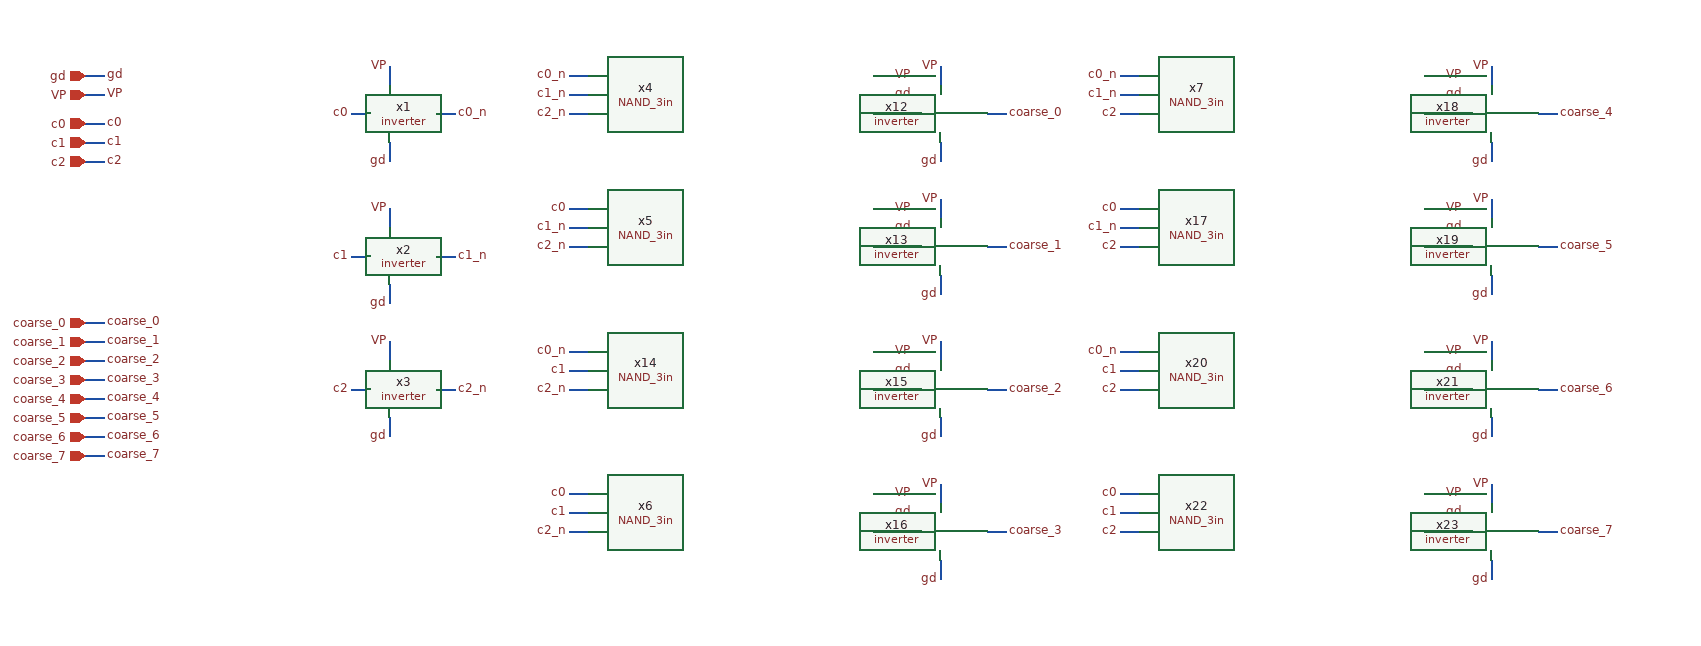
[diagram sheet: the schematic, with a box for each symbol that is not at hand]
v {xschem version=3.4.8RC file_version=1.3}
G {}
K {}
V {}
S {}
F {}
E {}
N 70 -40 90 -40 {lab=gd}
N 70 -20 90 -20 {lab=VP}
N 70 30 90 30 {lab=c1}
N 70 50 90 50 {lab=c2}
N 70 10 90 10 {lab=c0}
N 70 240 90 240 {lab=coarse_1}
N 70 260 90 260 {lab=coarse_2}
N 70 220 90 220 {lab=coarse_0}
N 70 280 90 280 {lab=coarse_3}
N 70 300 90 300 {lab=coarse_4}
N 70 340 90 340 {lab=coarse_6}
N 70 360 90 360 {lab=coarse_7}
N 70 320 90 320 {lab=coarse_5}
N 390 30 390 50 {lab=gd}
N 390 -50 390 -30 {lab=VP}
N 390 180 390 200 {lab=gd}
N 390 100 390 120 {lab=VP}
N 390 320 390 340 {lab=gd}
N 390 240 390 260 {lab=VP}
N 350 150 370 150 {lab=c1}
N 350 290 370 290 {lab=c2}
N 350 0 370 0 {lab=c0}
N 440 150 460 150 {lab=c1_n}
N 440 290 460 290 {lab=c2_n}
N 440 0 460 0 {lab=c0_n}
N 900 -40 920 -40 {lab=VP}
N 900 -20 920 -20 {lab=gd}
N 900 0 950 0 {lab=#net1}
N 580 -40 600 -40 {lab=c0_n}
N 580 -20 600 -20 {lab=c1_n}
N 580 0 600 0 {lab=c2_n}
N 900 100 920 100 {lab=VP}
N 900 120 920 120 {lab=gd}
N 900 140 950 140 {lab=#net2}
N 580 100 600 100 {lab=c0}
N 580 120 600 120 {lab=c1_n}
N 580 140 600 140 {lab=c2_n}
N 580 250 600 250 {lab=c0_n}
N 580 270 600 270 {lab=c1}
N 580 290 600 290 {lab=c2_n}
N 580 400 600 400 {lab=c0}
N 580 420 600 420 {lab=c1}
N 580 440 600 440 {lab=c2_n}
N 1160 100 1180 100 {lab=c0}
N 1160 120 1180 120 {lab=c1_n}
N 1160 140 1180 140 {lab=c2}
N 1160 250 1180 250 {lab=c0_n}
N 1160 270 1180 270 {lab=c1}
N 1160 290 1180 290 {lab=c2}
N 1160 400 1180 400 {lab=c0}
N 1160 420 1180 420 {lab=c1}
N 1160 440 1180 440 {lab=c2}
N 970 30 970 50 {lab=gd}
N 970 -50 970 -30 {lab=VP}
N 1020 0 1040 0 {lab=coarse_0}
N 970 170 970 190 {lab=gd}
N 970 90 970 110 {lab=VP}
N 1020 140 1040 140 {lab=coarse_1}
N 900 250 920 250 {lab=VP}
N 900 270 920 270 {lab=gd}
N 900 290 950 290 {lab=#net3}
N 970 320 970 340 {lab=gd}
N 970 240 970 260 {lab=VP}
N 1020 290 1040 290 {lab=coarse_2}
N 900 400 920 400 {lab=VP}
N 900 420 920 420 {lab=gd}
N 900 440 950 440 {lab=#net4}
N 970 470 970 490 {lab=gd}
N 970 390 970 410 {lab=VP}
N 1020 440 1040 440 {lab=coarse_3}
N 1480 -40 1500 -40 {lab=VP}
N 1480 -20 1500 -20 {lab=gd}
N 1480 0 1530 0 {lab=#net5}
N 1480 100 1500 100 {lab=VP}
N 1480 120 1500 120 {lab=gd}
N 1480 140 1530 140 {lab=#net6}
N 1550 30 1550 50 {lab=gd}
N 1550 -50 1550 -30 {lab=VP}
N 1600 0 1620 0 {lab=coarse_4}
N 1550 170 1550 190 {lab=gd}
N 1550 90 1550 110 {lab=VP}
N 1600 140 1620 140 {lab=coarse_5}
N 1480 250 1500 250 {lab=VP}
N 1480 270 1500 270 {lab=gd}
N 1480 290 1530 290 {lab=#net7}
N 1550 320 1550 340 {lab=gd}
N 1550 240 1550 260 {lab=VP}
N 1600 290 1620 290 {lab=coarse_6}
N 1480 400 1500 400 {lab=VP}
N 1480 420 1500 420 {lab=gd}
N 1480 440 1530 440 {lab=#net8}
N 1550 470 1550 490 {lab=gd}
N 1550 390 1550 410 {lab=VP}
N 1600 440 1620 440 {lab=coarse_7}
N 1160 -40 1180 -40 {lab=c0_n}
N 1160 -20 1180 -20 {lab=c1_n}
N 1160 0 1180 0 {lab=c2}
C {iopin.sym} 70 -40 2 0 {name=p46 lab=gd}
C {lab_wire.sym} 90 -40 2 0 {name=p53 sig_type=std_logic lab=gd}
C {iopin.sym} 70 -20 2 0 {name=p54 lab=VP}
C {ipin.sym} 70 30 0 0 {name=p2 lab=c1}
C {lab_wire.sym} 90 30 2 0 {name=p56 sig_type=std_logic lab=c1}
C {ipin.sym} 70 50 0 0 {name=p57 lab=c2}
C {lab_wire.sym} 90 50 2 0 {name=p58 sig_type=std_logic lab=c2}
C {ipin.sym} 70 10 0 0 {name=p20 lab=c0}
C {lab_wire.sym} 90 10 2 0 {name=p21 sig_type=std_logic lab=c0}
C {lab_wire.sym} 90 -20 2 0 {name=p1 sig_type=std_logic lab=VP}
C {opin.sym} 70 240 0 1 {name=p6 lab=coarse_1}
C {opin.sym} 70 260 0 1 {name=p8 lab=coarse_2}
C {opin.sym} 70 220 0 1 {name=p14 lab=coarse_0}
C {opin.sym} 70 280 0 1 {name=p10 lab=coarse_3}
C {opin.sym} 70 300 0 1 {name=p12 lab=coarse_4}
C {opin.sym} 70 320 0 1 {name=p3 lab=coarse_5}
C {opin.sym} 70 340 0 1 {name=p5 lab=coarse_6}
C {opin.sym} 70 360 0 1 {name=p17 lab=coarse_7}
C {/foss/designs/CHIP-PLL/schematics/divider/schematics/inverter.sym} 390 0 0 0 {name=x1}
C {lab_wire.sym} 390 50 3 0 {name=p29 sig_type=std_logic lab=gd}
C {lab_wire.sym} 390 -50 1 0 {name=p31 sig_type=std_logic lab=VP}
C {/foss/designs/CHIP-PLL/schematics/divider/schematics/inverter.sym} 390 150 0 0 {name=x2}
C {lab_wire.sym} 390 200 3 0 {name=p32 sig_type=std_logic lab=gd}
C {lab_wire.sym} 390 100 1 0 {name=p34 sig_type=std_logic lab=VP}
C {/foss/designs/CHIP-PLL/schematics/divider/schematics/inverter.sym} 390 290 0 0 {name=x3}
C {lab_wire.sym} 390 340 3 0 {name=p35 sig_type=std_logic lab=gd}
C {lab_wire.sym} 390 240 1 0 {name=p37 sig_type=std_logic lab=VP}
C {lab_wire.sym} 350 150 0 0 {name=p38 sig_type=std_logic lab=c1}
C {lab_wire.sym} 350 290 0 0 {name=p39 sig_type=std_logic lab=c2}
C {lab_wire.sym} 350 0 0 0 {name=p40 sig_type=std_logic lab=c0}
C {lab_wire.sym} 460 150 0 1 {name=p41 sig_type=std_logic lab=c1_n}
C {lab_wire.sym} 460 290 0 1 {name=p42 sig_type=std_logic lab=c2_n}
C {lab_wire.sym} 460 0 0 1 {name=p43 sig_type=std_logic lab=c0_n}
C {/foss/designs/CHIP-PLL/schematics/divider/schematics/NAND_3in.sym} 750 -20 0 0 {name=x4}
C {lab_wire.sym} 920 -40 2 0 {name=p30 sig_type=std_logic lab=VP}
C {lab_wire.sym} 920 -20 2 0 {name=p44 sig_type=std_logic lab=gd}
C {lab_wire.sym} 1040 0 2 0 {name=p45 sig_type=std_logic lab=coarse_0}
C {/foss/designs/CHIP-PLL/schematics/divider/schematics/NAND_3in.sym} 750 120 0 0 {name=x5}
C {lab_wire.sym} 920 100 2 0 {name=p47 sig_type=std_logic lab=VP}
C {lab_wire.sym} 920 120 2 0 {name=p48 sig_type=std_logic lab=gd}
C {lab_wire.sym} 1040 140 2 0 {name=p49 sig_type=std_logic lab=coarse_1}
C {lab_wire.sym} 1040 290 2 0 {name=p52 sig_type=std_logic lab=coarse_2}
C {lab_wire.sym} 1040 440 2 0 {name=p65 sig_type=std_logic lab=coarse_3}
C {lab_wire.sym} 1620 0 2 0 {name=p68 sig_type=std_logic lab=coarse_4}
C {lab_wire.sym} 1620 140 2 0 {name=p71 sig_type=std_logic lab=coarse_5}
C {lab_wire.sym} 1620 290 2 0 {name=p74 sig_type=std_logic lab=coarse_6}
C {lab_wire.sym} 1620 440 2 0 {name=p77 sig_type=std_logic lab=coarse_7}
C {lab_wire.sym} 580 -40 2 1 {name=p78 sig_type=std_logic lab=c0_n}
C {lab_wire.sym} 580 -20 2 1 {name=p79 sig_type=std_logic lab=c1_n}
C {lab_wire.sym} 580 0 2 1 {name=p80 sig_type=std_logic lab=c2_n}
C {lab_wire.sym} 580 100 2 1 {name=p81 sig_type=std_logic lab=c0}
C {lab_wire.sym} 580 120 2 1 {name=p82 sig_type=std_logic lab=c1_n}
C {lab_wire.sym} 580 140 2 1 {name=p83 sig_type=std_logic lab=c2_n}
C {lab_wire.sym} 580 270 2 1 {name=p84 sig_type=std_logic lab=c1}
C {lab_wire.sym} 580 250 2 1 {name=p85 sig_type=std_logic lab=c0_n}
C {lab_wire.sym} 580 290 2 1 {name=p86 sig_type=std_logic lab=c2_n}
C {lab_wire.sym} 580 440 2 1 {name=p87 sig_type=std_logic lab=c2_n}
C {lab_wire.sym} 580 400 2 1 {name=p88 sig_type=std_logic lab=c0}
C {lab_wire.sym} 580 420 2 1 {name=p89 sig_type=std_logic lab=c1}
C {lab_wire.sym} 1160 100 2 1 {name=p93 sig_type=std_logic lab=c0}
C {lab_wire.sym} 1160 140 2 1 {name=p94 sig_type=std_logic lab=c2}
C {lab_wire.sym} 1160 120 2 1 {name=p95 sig_type=std_logic lab=c1_n}
C {lab_wire.sym} 1160 290 2 1 {name=p96 sig_type=std_logic lab=c2}
C {lab_wire.sym} 1160 440 2 1 {name=p97 sig_type=std_logic lab=c2}
C {lab_wire.sym} 1160 270 2 1 {name=p98 sig_type=std_logic lab=c1}
C {lab_wire.sym} 1160 420 2 1 {name=p99 sig_type=std_logic lab=c1}
C {lab_wire.sym} 1160 400 2 1 {name=p100 sig_type=std_logic lab=c0}
C {lab_wire.sym} 1160 250 2 1 {name=p101 sig_type=std_logic lab=c0_n}
C {/foss/designs/CHIP-PLL/schematics/divider/schematics/inverter.sym} 970 0 0 0 {name=x12}
C {lab_wire.sym} 970 50 3 0 {name=p102 sig_type=std_logic lab=gd}
C {lab_wire.sym} 970 -50 1 0 {name=p103 sig_type=std_logic lab=VP}
C {/foss/designs/CHIP-PLL/schematics/divider/schematics/inverter.sym} 970 140 0 0 {name=x13}
C {lab_wire.sym} 970 190 3 0 {name=p104 sig_type=std_logic lab=gd}
C {lab_wire.sym} 970 90 1 0 {name=p105 sig_type=std_logic lab=VP}
C {/foss/designs/CHIP-PLL/schematics/divider/schematics/NAND_3in.sym} 750 270 0 0 {name=x14}
C {lab_wire.sym} 920 250 2 0 {name=p106 sig_type=std_logic lab=VP}
C {lab_wire.sym} 920 270 2 0 {name=p107 sig_type=std_logic lab=gd}
C {/foss/designs/CHIP-PLL/schematics/divider/schematics/inverter.sym} 970 290 0 0 {name=x15}
C {lab_wire.sym} 970 340 3 0 {name=p108 sig_type=std_logic lab=gd}
C {lab_wire.sym} 970 240 1 0 {name=p109 sig_type=std_logic lab=VP}
C {/foss/designs/CHIP-PLL/schematics/divider/schematics/NAND_3in.sym} 750 420 0 0 {name=x6}
C {lab_wire.sym} 920 400 2 0 {name=p50 sig_type=std_logic lab=VP}
C {lab_wire.sym} 920 420 2 0 {name=p51 sig_type=std_logic lab=gd}
C {/foss/designs/CHIP-PLL/schematics/divider/schematics/inverter.sym} 970 440 0 0 {name=x16}
C {lab_wire.sym} 970 490 3 0 {name=p110 sig_type=std_logic lab=gd}
C {lab_wire.sym} 970 390 1 0 {name=p111 sig_type=std_logic lab=VP}
C {/foss/designs/CHIP-PLL/schematics/divider/schematics/NAND_3in.sym} 1330 -20 0 0 {name=x7}
C {lab_wire.sym} 1500 -40 2 0 {name=p62 sig_type=std_logic lab=VP}
C {lab_wire.sym} 1500 -20 2 0 {name=p64 sig_type=std_logic lab=gd}
C {/foss/designs/CHIP-PLL/schematics/divider/schematics/NAND_3in.sym} 1330 120 0 0 {name=x17}
C {lab_wire.sym} 1500 100 2 0 {name=p113 sig_type=std_logic lab=VP}
C {lab_wire.sym} 1500 120 2 0 {name=p114 sig_type=std_logic lab=gd}
C {/foss/designs/CHIP-PLL/schematics/divider/schematics/inverter.sym} 1550 0 0 0 {name=x18}
C {lab_wire.sym} 1550 50 3 0 {name=p130 sig_type=std_logic lab=gd}
C {lab_wire.sym} 1550 -50 1 0 {name=p131 sig_type=std_logic lab=VP}
C {/foss/designs/CHIP-PLL/schematics/divider/schematics/inverter.sym} 1550 140 0 0 {name=x19}
C {lab_wire.sym} 1550 190 3 0 {name=p132 sig_type=std_logic lab=gd}
C {lab_wire.sym} 1550 90 1 0 {name=p133 sig_type=std_logic lab=VP}
C {/foss/designs/CHIP-PLL/schematics/divider/schematics/NAND_3in.sym} 1330 270 0 0 {name=x20}
C {lab_wire.sym} 1500 250 2 0 {name=p134 sig_type=std_logic lab=VP}
C {lab_wire.sym} 1500 270 2 0 {name=p135 sig_type=std_logic lab=gd}
C {/foss/designs/CHIP-PLL/schematics/divider/schematics/inverter.sym} 1550 290 0 0 {name=x21}
C {lab_wire.sym} 1550 340 3 0 {name=p136 sig_type=std_logic lab=gd}
C {lab_wire.sym} 1550 240 1 0 {name=p137 sig_type=std_logic lab=VP}
C {/foss/designs/CHIP-PLL/schematics/divider/schematics/NAND_3in.sym} 1330 420 0 0 {name=x22}
C {lab_wire.sym} 1500 400 2 0 {name=p138 sig_type=std_logic lab=VP}
C {lab_wire.sym} 1500 420 2 0 {name=p139 sig_type=std_logic lab=gd}
C {/foss/designs/CHIP-PLL/schematics/divider/schematics/inverter.sym} 1550 440 0 0 {name=x23}
C {lab_wire.sym} 1550 490 3 0 {name=p140 sig_type=std_logic lab=gd}
C {lab_wire.sym} 1550 390 1 0 {name=p141 sig_type=std_logic lab=VP}
C {lab_wire.sym} 1160 0 2 1 {name=p112 sig_type=std_logic lab=c2}
C {lab_wire.sym} 1160 -40 2 1 {name=p115 sig_type=std_logic lab=c0_n}
C {lab_wire.sym} 1160 -20 2 1 {name=p116 sig_type=std_logic lab=c1_n}
C {lab_wire.sym} 90 220 2 0 {name=p4 sig_type=std_logic lab=coarse_0}
C {lab_wire.sym} 90 240 2 0 {name=p7 sig_type=std_logic lab=coarse_1}
C {lab_wire.sym} 90 260 2 0 {name=p9 sig_type=std_logic lab=coarse_2}
C {lab_wire.sym} 90 280 2 0 {name=p11 sig_type=std_logic lab=coarse_3}
C {lab_wire.sym} 90 300 2 0 {name=p13 sig_type=std_logic lab=coarse_4}
C {lab_wire.sym} 90 320 2 0 {name=p15 sig_type=std_logic lab=coarse_5}
C {lab_wire.sym} 90 340 2 0 {name=p16 sig_type=std_logic lab=coarse_6}
C {lab_wire.sym} 90 360 2 0 {name=p18 sig_type=std_logic lab=coarse_7}
